VERSION 5.7 ;
  NOWIREEXTENSIONATPIN ON ;
  DIVIDERCHAR "/" ;
  BUSBITCHARS "[]" ;
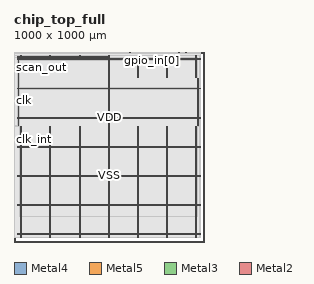
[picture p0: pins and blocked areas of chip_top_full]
MACRO chip_top_full
  CLASS BLOCK ;
  FOREIGN chip_top_full ;
  ORIGIN 0.000 0.000 ;
  SIZE 1000.000 BY 1000.000 ;
  PIN VDD
    DIRECTION INOUT ;
    USE POWER ;
    PORT
      LAYER Metal4 ;
        RECT 35.680 23.220 37.280 609.720 ;
    END
    PORT
      LAYER Metal4 ;
        RECT 35.680 971.160 37.280 980.300 ;
    END
    PORT
      LAYER Metal4 ;
        RECT 189.280 23.220 190.880 609.720 ;
    END
    PORT
      LAYER Metal4 ;
        RECT 189.280 971.160 190.880 980.300 ;
    END
    PORT
      LAYER Metal4 ;
        RECT 342.880 23.220 344.480 609.720 ;
    END
    PORT
      LAYER Metal4 ;
        RECT 342.880 971.160 344.480 980.300 ;
    END
    PORT
      LAYER Metal4 ;
        RECT 496.480 23.220 498.080 980.300 ;
    END
    PORT
      LAYER Metal4 ;
        RECT 650.080 23.220 651.680 609.720 ;
    END
    PORT
      LAYER Metal4 ;
        RECT 650.080 863.160 651.680 980.300 ;
    END
    PORT
      LAYER Metal4 ;
        RECT 803.680 23.220 805.280 609.720 ;
    END
    PORT
      LAYER Metal4 ;
        RECT 803.680 863.160 805.280 980.300 ;
    END
    PORT
      LAYER Metal4 ;
        RECT 957.280 23.220 958.880 609.720 ;
    END
    PORT
      LAYER Metal4 ;
        RECT 957.280 863.160 958.880 980.300 ;
    END
    PORT
      LAYER Metal5 ;
        RECT 20.160 39.370 980.000 40.970 ;
    END
    PORT
      LAYER Metal5 ;
        RECT 20.160 192.550 980.000 194.150 ;
    END
    PORT
      LAYER Metal5 ;
        RECT 20.160 345.730 980.000 347.330 ;
    END
    PORT
      LAYER Metal5 ;
        RECT 20.160 498.910 980.000 500.510 ;
    END
    PORT
      LAYER Metal5 ;
        RECT 20.160 652.090 980.000 653.690 ;
    END
    PORT
      LAYER Metal5 ;
        RECT 20.160 805.270 980.000 806.870 ;
    END
    PORT
      LAYER Metal5 ;
        RECT 20.160 958.450 980.000 960.050 ;
    END
    PORT
      LAYER Metal4 ;
        RECT 21.320 611.220 22.920 972.460 ;
    END
    PORT
      LAYER Metal4 ;
        RECT 965.480 611.220 967.080 862.700 ;
    END
    PORT
      LAYER Metal5 ;
        RECT 20.160 973.450 501.380 975.050 ;
    END
  END VDD
  PIN VSS
    DIRECTION INOUT ;
    USE GROUND ;
    PORT
      LAYER Metal4 ;
        RECT 38.980 23.220 40.580 609.720 ;
    END
    PORT
      LAYER Metal4 ;
        RECT 38.980 971.160 40.580 980.300 ;
    END
    PORT
      LAYER Metal4 ;
        RECT 192.580 23.220 194.180 609.720 ;
    END
    PORT
      LAYER Metal4 ;
        RECT 192.580 971.160 194.180 980.300 ;
    END
    PORT
      LAYER Metal4 ;
        RECT 346.180 23.220 347.780 609.720 ;
    END
    PORT
      LAYER Metal4 ;
        RECT 346.180 971.160 347.780 980.300 ;
    END
    PORT
      LAYER Metal4 ;
        RECT 499.780 23.220 501.380 980.300 ;
    END
    PORT
      LAYER Metal4 ;
        RECT 653.380 23.220 654.980 609.720 ;
    END
    PORT
      LAYER Metal4 ;
        RECT 653.380 863.160 654.980 980.300 ;
    END
    PORT
      LAYER Metal4 ;
        RECT 806.980 23.220 808.580 609.720 ;
    END
    PORT
      LAYER Metal4 ;
        RECT 806.980 863.160 808.580 980.300 ;
    END
    PORT
      LAYER Metal4 ;
        RECT 960.580 23.220 962.180 609.720 ;
    END
    PORT
      LAYER Metal4 ;
        RECT 960.580 863.160 962.180 980.300 ;
    END
    PORT
      LAYER Metal5 ;
        RECT 20.160 42.670 980.000 44.270 ;
    END
    PORT
      LAYER Metal5 ;
        RECT 20.160 195.850 980.000 197.450 ;
    END
    PORT
      LAYER Metal5 ;
        RECT 20.160 349.030 980.000 350.630 ;
    END
    PORT
      LAYER Metal5 ;
        RECT 20.160 502.210 980.000 503.810 ;
    END
    PORT
      LAYER Metal5 ;
        RECT 20.160 655.390 980.000 656.990 ;
    END
    PORT
      LAYER Metal5 ;
        RECT 20.160 808.570 980.000 810.170 ;
    END
    PORT
      LAYER Metal5 ;
        RECT 20.160 961.750 980.000 963.350 ;
    END
    PORT
      LAYER Metal4 ;
        RECT 24.680 611.220 26.280 972.460 ;
    END
    PORT
      LAYER Metal4 ;
        RECT 968.840 611.220 970.440 862.700 ;
    END
    PORT
      LAYER Metal5 ;
        RECT 20.160 977.050 501.380 978.650 ;
    END
  END VSS
  PIN clk
    DIRECTION INPUT ;
    USE SIGNAL ;
    ANTENNAGATEAREA 9.476000 ;
    PORT
      LAYER Metal3 ;
        RECT 0.000 742.560 0.560 743.120 ;
    END
  END clk
  PIN clk_int
    DIRECTION INPUT ;
    USE SIGNAL ;
    ANTENNAGATEAREA 0.396000 ;
    PORT
      LAYER Metal3 ;
        RECT 0.000 540.960 0.560 541.520 ;
    END
  END clk_int
  PIN gpio_in[0]
    DIRECTION INPUT ;
    USE SIGNAL ;
    ANTENNAGATEAREA 0.396000 ;
    PORT
      LAYER Metal2 ;
        RECT 728.000 999.440 728.560 1000.000 ;
    END
  END gpio_in[0]
  PIN gpio_in[1]
    DIRECTION INPUT ;
    USE SIGNAL ;
    ANTENNAGATEAREA 0.396000 ;
    PORT
      LAYER Metal2 ;
        RECT 707.840 999.440 708.400 1000.000 ;
    END
  END gpio_in[1]
  PIN gpio_out[0]
    DIRECTION OUTPUT ;
    USE SIGNAL ;
    ANTENNADIFFAREA 0.897600 ;
    PORT
      LAYER Metal2 ;
        RECT 787.360 999.440 787.920 1000.000 ;
    END
  END gpio_out[0]
  PIN gpio_out[1]
    DIRECTION OUTPUT ;
    USE SIGNAL ;
    ANTENNADIFFAREA 0.897600 ;
    PORT
      LAYER Metal2 ;
        RECT 777.280 999.440 777.840 1000.000 ;
    END
  END gpio_out[1]
  PIN gpio_out[2]
    DIRECTION OUTPUT ;
    USE SIGNAL ;
    ANTENNADIFFAREA 0.897600 ;
    PORT
      LAYER Metal2 ;
        RECT 766.080 999.440 766.640 1000.000 ;
    END
  END gpio_out[2]
  PIN gpio_out[3]
    DIRECTION OUTPUT ;
    USE SIGNAL ;
    ANTENNADIFFAREA 0.897600 ;
    PORT
      LAYER Metal2 ;
        RECT 767.200 999.440 767.760 1000.000 ;
    END
  END gpio_out[3]
  PIN gpio_out[4]
    DIRECTION OUTPUT ;
    USE SIGNAL ;
    ANTENNADIFFAREA 0.897600 ;
    PORT
      LAYER Metal2 ;
        RECT 790.720 999.440 791.280 1000.000 ;
    END
  END gpio_out[4]
  PIN rst_n
    DIRECTION INPUT ;
    USE SIGNAL ;
    ANTENNAGATEAREA 4.408000 ;
    PORT
      LAYER Metal2 ;
        RECT 917.280 999.440 917.840 1000.000 ;
    END
  END rst_n
  PIN scan_i0o1
    DIRECTION INPUT ;
    USE SIGNAL ;
    ANTENNAGATEAREA 0.396000 ;
    PORT
      LAYER Metal3 ;
        RECT 0.000 544.320 0.560 544.880 ;
    END
  END scan_i0o1
  PIN scan_in
    DIRECTION INPUT ;
    USE SIGNAL ;
    ANTENNAGATEAREA 0.396000 ;
    PORT
      LAYER Metal3 ;
        RECT 0.000 537.600 0.560 538.160 ;
    END
  END scan_in
  PIN scan_load
    DIRECTION INPUT ;
    USE SIGNAL ;
    ANTENNAGATEAREA 0.396000 ;
    PORT
      LAYER Metal3 ;
        RECT 0.000 545.440 0.560 546.000 ;
    END
  END scan_load
  PIN scan_out
    DIRECTION OUTPUT ;
    USE SIGNAL ;
    ANTENNADIFFAREA 0.897600 ;
    PORT
      LAYER Metal3 ;
        RECT 0.000 919.520 0.560 920.080 ;
    END
  END scan_out
  PIN scan_shift
    DIRECTION INPUT ;
    USE SIGNAL ;
    ANTENNAGATEAREA 0.396000 ;
    PORT
      LAYER Metal3 ;
        RECT 0.000 548.800 0.560 549.360 ;
    END
  END scan_shift
  PIN spi_cs_n
    DIRECTION OUTPUT ;
    USE SIGNAL ;
    ANTENNADIFFAREA 0.897600 ;
    PORT
      LAYER Metal2 ;
        RECT 904.960 999.440 905.520 1000.000 ;
    END
  END spi_cs_n
  PIN spi_mosi
    DIRECTION OUTPUT ;
    USE SIGNAL ;
    ANTENNADIFFAREA 0.897600 ;
    PORT
      LAYER Metal2 ;
        RECT 868.000 999.440 868.560 1000.000 ;
    END
  END spi_mosi
  PIN spi_sclk
    DIRECTION OUTPUT ;
    USE SIGNAL ;
    ANTENNADIFFAREA 0.897600 ;
    PORT
      LAYER Metal2 ;
        RECT 908.320 999.440 908.880 1000.000 ;
    END
  END spi_sclk
  PIN uart_rx
    DIRECTION INPUT ;
    USE SIGNAL ;
    ANTENNAGATEAREA 0.396000 ;
    PORT
      LAYER Metal2 ;
        RECT 610.400 999.440 610.960 1000.000 ;
    END
  END uart_rx
  PIN uart_tx
    DIRECTION OUTPUT ;
    USE SIGNAL ;
    ANTENNADIFFAREA 0.897600 ;
    PORT
      LAYER Metal2 ;
        RECT 854.560 999.440 855.120 1000.000 ;
    END
  END uart_tx
  OBS
      LAYER Nwell ;
        RECT 19.730 23.090 980.430 980.430 ;
      LAYER Metal1 ;
        RECT 20.160 23.220 980.000 980.300 ;
      LAYER Metal2 ;
        RECT 3.500 999.140 610.100 999.860 ;
        RECT 611.260 999.140 707.540 999.860 ;
        RECT 708.700 999.140 727.700 999.860 ;
        RECT 728.860 999.140 765.780 999.860 ;
        RECT 768.060 999.140 776.980 999.860 ;
        RECT 778.140 999.140 787.060 999.860 ;
        RECT 788.220 999.140 790.420 999.860 ;
        RECT 791.580 999.140 854.260 999.860 ;
        RECT 855.420 999.140 867.700 999.860 ;
        RECT 868.860 999.140 904.660 999.860 ;
        RECT 905.820 999.140 908.020 999.860 ;
        RECT 909.180 999.140 916.980 999.860 ;
        RECT 918.140 999.140 983.220 999.860 ;
        RECT 3.500 23.330 983.220 999.140 ;
      LAYER Metal3 ;
        RECT 0.560 920.380 983.270 991.060 ;
        RECT 0.860 919.220 983.270 920.380 ;
        RECT 0.560 743.420 983.270 919.220 ;
        RECT 0.860 742.260 983.270 743.420 ;
        RECT 0.560 549.660 983.270 742.260 ;
        RECT 0.860 548.500 983.270 549.660 ;
        RECT 0.560 546.300 983.270 548.500 ;
        RECT 0.860 544.020 983.270 546.300 ;
        RECT 0.560 541.820 983.270 544.020 ;
        RECT 0.860 540.660 983.270 541.820 ;
        RECT 0.560 538.460 983.270 540.660 ;
        RECT 0.860 537.300 983.270 538.460 ;
        RECT 0.560 23.380 983.270 537.300 ;
      LAYER Metal4 ;
        RECT 0.700 980.600 976.500 981.590 ;
        RECT 0.700 972.760 35.380 980.600 ;
        RECT 0.700 610.920 21.020 972.760 ;
        RECT 23.220 610.920 24.380 972.760 ;
        RECT 26.580 970.860 35.380 972.760 ;
        RECT 37.580 970.860 38.680 980.600 ;
        RECT 40.880 970.860 188.980 980.600 ;
        RECT 191.180 970.860 192.280 980.600 ;
        RECT 194.480 970.860 342.580 980.600 ;
        RECT 344.780 970.860 345.880 980.600 ;
        RECT 348.080 970.860 496.180 980.600 ;
        RECT 26.580 610.920 496.180 970.860 ;
        RECT 0.700 610.020 496.180 610.920 ;
        RECT 0.700 23.610 35.380 610.020 ;
        RECT 37.580 23.610 38.680 610.020 ;
        RECT 40.880 23.610 188.980 610.020 ;
        RECT 191.180 23.610 192.280 610.020 ;
        RECT 194.480 23.610 342.580 610.020 ;
        RECT 344.780 23.610 345.880 610.020 ;
        RECT 348.080 23.610 496.180 610.020 ;
        RECT 498.380 23.610 499.480 980.600 ;
        RECT 501.680 862.860 649.780 980.600 ;
        RECT 651.980 862.860 653.080 980.600 ;
        RECT 655.280 862.860 803.380 980.600 ;
        RECT 805.580 862.860 806.680 980.600 ;
        RECT 808.880 862.860 956.980 980.600 ;
        RECT 959.180 862.860 960.280 980.600 ;
        RECT 962.480 863.000 976.500 980.600 ;
        RECT 962.480 862.860 965.180 863.000 ;
        RECT 501.680 610.920 965.180 862.860 ;
        RECT 967.380 610.920 968.540 863.000 ;
        RECT 970.740 610.920 976.500 863.000 ;
        RECT 501.680 610.020 976.500 610.920 ;
        RECT 501.680 23.610 649.780 610.020 ;
        RECT 651.980 23.610 653.080 610.020 ;
        RECT 655.280 23.610 803.380 610.020 ;
        RECT 805.580 23.610 806.680 610.020 ;
        RECT 808.880 23.610 956.980 610.020 ;
        RECT 959.180 23.610 960.280 610.020 ;
        RECT 962.480 23.610 976.500 610.020 ;
      LAYER Metal5 ;
        RECT 27.500 963.950 968.180 972.670 ;
        RECT 27.500 960.650 968.180 961.150 ;
        RECT 27.500 810.770 968.180 957.850 ;
        RECT 27.500 807.470 968.180 807.970 ;
        RECT 27.500 657.590 968.180 804.670 ;
        RECT 27.500 654.290 968.180 654.790 ;
        RECT 27.500 504.410 968.180 651.490 ;
        RECT 27.500 501.110 968.180 501.610 ;
        RECT 27.500 351.230 968.180 498.310 ;
        RECT 27.500 347.930 968.180 348.430 ;
        RECT 27.500 198.050 968.180 345.130 ;
        RECT 27.500 194.750 968.180 195.250 ;
        RECT 27.500 134.330 968.180 191.950 ;
  END
END chip_top_full
END LIBRARY

